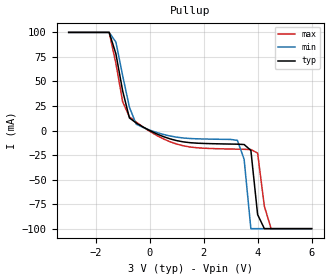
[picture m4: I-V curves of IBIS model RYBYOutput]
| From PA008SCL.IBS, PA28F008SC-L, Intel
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|****************Ready/Busy Output Model*****************************
[Model]   RYBYOutput
Model_type   Output
|   For RY/BY#
Vinl = 0.8V
Vinh = 2.0V
| Variable   typ   min   max
C_comp   9.61p   NA   11.6p
[Voltage Range]   3.0V   2.7V   3.3V
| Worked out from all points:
|   slope of the pullup table from 0 to 0.45 V, typ, clamps not added: 81.3 ohm
[Pulldown]
| [Pullup] and [Pulldown] IV curves include only the current through
| the channels of output driver transistors when outputs are enabled
| with OE# = VIL.  Although the output driver transistors have np and
| pn diodes inherently created by CMOS IC fabrication between the
| drain and bulk of n-channel and p-channel CMOS transistors,
| the current through these junction diodes is not included in
| [Pullup] or [Pulldown].  Instead that drain/bulk diode current is
| included in the [POWER_clamp] or [GND_clamp] sections, which are
| not dependent on the state of OE# or output data value.  The RY/BY#
| Pulldown information is not provided for this device.  The table
| below is for the compatibility with some IBIS parsers.
|Voltage   I(typ)   I(min)   I(max)
-3V       0A         0A         0A
0V        0A         0A         0A
3V        0A         0A         0A
6V        0A         0A         0A
[GND_clamp]
| The RY/BY# pin is always active and does NOT float to tri-state when
| the chip is deselected or when the data outputs are disabled.
| Therefore, the table below is included for the compatibility with
| some IBIS parsers.
|Voltage   I(typ)   I(min)   I(max)
-3V       0A         0A         0A
0V        0A         0A         0A
3V        0A         0A         0A
6V        0A         0A         0A
[Pullup]
| (Voltages for [Pullup] and [POWER_clamp] are specified with
| negative respect to Vcc.  Reference the IBIS documentation
| for more information regarding Vtable = Vcc - Voutput.
| This method keeps -Vds constant for the values in all three
| columns across a line of the table.)
| [Pullup] and [Pulldown] IV curves include only the current through
| the channels of output driver transistors when outputs are enabled
| with OE# = VIL.  Although the output driver transistors have np and
| pn diodes inherently created by CMOS IC fabrication between the
| drain and bulk of n-channel and p-channel CMOS transistors,
| the current through these junction diodes is not included in
| [Pullup] or [Pulldown].  Instead that drain/bulk diode current is
| included in the [POWER_clamp] or [GND_clamp] sections, which are
| not dependent on the state of OE# or output data value.
|Voltage  I(typ)   I(min)   I(max)
-3V       100mA      100mA      100mA
-1.5V     100mA      100mA      100mA
-1.25V    78.15mA    90.06mA    68.32mA
-1V       40.44mA    56mA       29.39mA
-500mV    7.829mA    6.54mA     8.679mA
3.25V     -13.82mA   -9.941mA   -18.92mA
3.5V      -14.19mA   -29.18mA   -19.04mA
3.75V     -20.15mA   -99.85mA   -19.29mA
4V        -85.51mA   -99.85mA   -22.91mA
4.25V     -99.85mA   -99.85mA   -77.06mA
4.5V      -99.85mA   -99.85mA   -99.85mA
6V        -99.85mA   -99.85mA   -99.85mA
[POWER_clamp]
| The RY/BY# pin is always active and does NOT float to tri-state when
| the chip is deselected or when the data outputs are disabled.
| Therefore, the table below is included for the compatibility with
| some IBIS parsers.
|Voltage  I(typ)   I(min)   I(max)
-3V       0A         0A         0A
0V        0A         0A         0A
3V        0A         0A         0A
6V        0A         0A         0A
[Ramp]
| The RY/BY# Ramp information is not provided for this device.  The table
| below is for the compatibility with some IBIS parsers.
| Variable   typ   min   max
 dV/dt_r   0V/0ns   0V/0ns   0V/0ns
 dV/dt_f   0V/0ns   0V/0ns   0V/0ns
